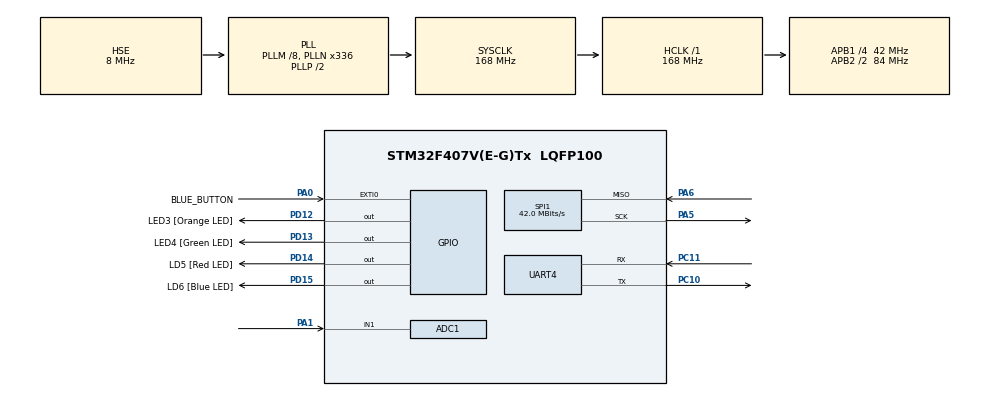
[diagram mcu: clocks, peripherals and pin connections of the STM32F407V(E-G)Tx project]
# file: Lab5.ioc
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ADC1.Channel-12\#ChannelRegularConversion=ADC_CHANNEL_1
ADC1.ClockPrescaler=ADC_CLOCK_SYNC_PCLK_DIV4
ADC1.ContinuousConvMode=DISABLE
ADC1.DMAContinuousRequests=DISABLE
ADC1.DataAlign=ADC_DATAALIGN_RIGHT
ADC1.DiscontinuousConvMode=DISABLE
ADC1.EOCSelection=ADC_EOC_SEQ_CONV
ADC1.EnableAnalogWatchDog=false
ADC1.ExternalTrigConv=ADC_EXTERNALTRIGCONV_T2_TRGO
ADC1.ExternalTrigConvEdge=ADC_EXTERNALTRIGCONVEDGE_RISING
ADC1.InjNumberOfConversion=0
ADC1.NbrOfConversion=1
ADC1.NbrOfConversionFlag=1
ADC1.Rank-12\#ChannelRegularConversion=1
ADC1.Resolution=ADC_RESOLUTION_12B
ADC1.SamplingTime-12\#ChannelRegularConversion=ADC_SAMPLETIME_480CYCLES
ADC1.ScanConvMode=DISABLE
ADC1.master=1
Dma.ADC1.0.Direction=DMA_PERIPH_TO_MEMORY
Dma.ADC1.0.FIFOMode=DMA_FIFOMODE_DISABLE
Dma.ADC1.0.Instance=DMA2_Stream0
Dma.ADC1.0.MemDataAlignment=DMA_MDATAALIGN_WORD
Dma.ADC1.0.MemInc=DMA_MINC_ENABLE
Dma.ADC1.0.Mode=DMA_CIRCULAR
Dma.ADC1.0.PeriphDataAlignment=DMA_PDATAALIGN_WORD
Dma.ADC1.0.PeriphInc=DMA_PINC_DISABLE
Dma.ADC1.0.Priority=DMA_PRIORITY_LOW
Dma.Request0=ADC1
Mcu.Family=STM32F4
Mcu.Name=STM32F407V(E-G)Tx
Mcu.Package=LQFP100
NVIC.ADC_IRQn=true\:0\:0\:false\:false\:true\:true
NVIC.DMA2_Stream0_IRQn=true\:0\:0\:false\:false\:true\:false
NVIC.EXTI0_IRQn=true\:0\:0\:false\:false\:true\:true
NVIC.PriorityGroup=NVIC_PRIORITYGROUP_4
NVIC.TIM2_IRQn=true\:0\:0\:true\:false\:true\:true
PA0-WKUP.GPIO_Label=BLUE_BUTTON
PA0-WKUP.Signal=GPXTI0
PA1.Signal=ADCx_IN1
PA5.Mode=RX_Only_Simplex_Unidirect_Master
PA5.Signal=SPI1_SCK
PA6.Mode=RX_Only_Simplex_Unidirect_Master
PA6.Signal=SPI1_MISO
PC10.Mode=Asynchronous
PC10.Signal=UART4_TX
PC11.Mode=Asynchronous
PC11.Signal=UART4_RX
PD12.GPIO_Label=LED3 [Orange LED]
PD12.Signal=GPIO_Output
PD13.GPIO_Label=LED4 [Green LED]
PD13.Signal=GPIO_Output
PD14.GPIO_Label=LD5 [Red LED]
PD14.Signal=GPIO_Output
PD15.GPIO_Label=LD6 [Blue LED]
PD15.Signal=GPIO_Output
PH0-OSC_IN.Mode=HSE-External-Oscillator
PH0-OSC_IN.Signal=RCC_OSC_IN
PH1-OSC_OUT.Mode=HSE-External-Oscillator
PH1-OSC_OUT.Signal=RCC_OSC_OUT
ProjectManager.HeapSize=0x200
ProjectManager.StackSize=0x400
ProjectManager.TargetToolchain=MDK-ARM V5
RCC.48MHZClocksFreq_Value=84000000
RCC.AHBFreq_Value=168000000
RCC.APB1CLKDivider=RCC_HCLK_DIV4
RCC.APB1Freq_Value=42000000
RCC.APB1TimFreq_Value=84000000
RCC.APB2CLKDivider=RCC_HCLK_DIV2
RCC.APB2Freq_Value=84000000
RCC.APB2TimFreq_Value=168000000
RCC.CortexFreq_Value=168000000
RCC.HCLKFreq_Value=168000000
RCC.HSE_VALUE=8000000
RCC.HSI_VALUE=16000000
RCC.LSE_VALUE=32768
RCC.PLLM=8
RCC.PLLN=336
RCC.PLLSourceVirtual=RCC_PLLSOURCE_HSE
RCC.SYSCLKFreq_VALUE=168000000
RCC.SYSCLKSource=RCC_SYSCLKSOURCE_PLLCLK
RCC.VCOOutputFreq_Value=336000000
SH.ADCx_IN1.0=ADC1_IN1,IN1
SPI1.CalculateBaudRate=42.0 MBits/s
SPI1.Direction=SPI_DIRECTION_2LINES_RXONLY
SPI1.Mode=SPI_MODE_MASTER
SPI1.VirtualType=VM_MASTER
TIM2.Period=1000
TIM2.Prescaler=1000
TIM2.TIM_MasterOutputTrigger=TIM_TRGO_UPDATE
UART4.VirtualMode=Asynchronous
VP_TIM2_VS_ClockSourceINT.Mode=Internal
board=Lab5

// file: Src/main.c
/**
  ******************************************************************************
  * File Name          : main.c
  * Description        : Main program body
  ******************************************************************************
  ** This notice applies to any and all portions of this file
  * that are not between comment pairs USER CODE BEGIN and
  * USER CODE END. Other portions of this file, whether
  * inserted by the user or by software development tools
  * are owned by their respective copyright owners.
  *
  * COPYRIGHT(c) 2018 STMicroelectronics
  *
  * Redistribution and use in source and binary forms, with or without modification,
  * are permitted provided that the following conditions are met:
  *   1. Redistributions of source code must retain the above copyright notice,
  *      this list of conditions and the following disclaimer.
  *   2. Redistributions in binary form must reproduce the above copyright notice,
  *      this list of conditions and the following disclaimer in the documentation
  *      and/or other materials provided with the distribution.
  *   3. Neither the name of STMicroelectronics nor the names of its contributors
  *      may be used to endorse or promote products derived from this software
  *      without specific prior written permission.
  *
  * THIS SOFTWARE IS PROVIDED BY THE COPYRIGHT HOLDERS AND CONTRIBUTORS "AS IS"
  * AND ANY EXPRESS OR IMPLIED WARRANTIES, INCLUDING, BUT NOT LIMITED TO, THE
  * IMPLIED WARRANTIES OF MERCHANTABILITY AND FITNESS FOR A PARTICULAR PURPOSE ARE
  * DISCLAIMED. IN NO EVENT SHALL THE COPYRIGHT HOLDER OR CONTRIBUTORS BE LIABLE
  * FOR ANY DIRECT, INDIRECT, INCIDENTAL, SPECIAL, EXEMPLARY, OR CONSEQUENTIAL
  * DAMAGES (INCLUDING, BUT NOT LIMITED TO, PROCUREMENT OF SUBSTITUTE GOODS OR
  * SERVICES; LOSS OF USE, DATA, OR PROFITS; OR BUSINESS INTERRUPTION) HOWEVER
  * CAUSED AND ON ANY THEORY OF LIABILITY, WHETHER IN CONTRACT, STRICT LIABILITY,
  * OR TORT (INCLUDING NEGLIGENCE OR OTHERWISE) ARISING IN ANY WAY OUT OF THE USE
  * OF THIS SOFTWARE, EVEN IF ADVISED OF THE POSSIBILITY OF SUCH DAMAGE.
  *
  ******************************************************************************
  */
#include "main.h"
#include "stm32f4xx_hal.h"
#include "lis3dsh.h"

#define STATE_NOTHING 0
#define STATE_TAP 1
#define STATE_DOUBLETAP 2
#define STATE_SINGLETAP 3

#define X_THRESH 100
#define Y_THRESH 100
#define Z_THRESH 30

#define ACC_SAMPLE_PERIOD_MS 1
#define FSM_FREQUENCY_MS 50
#define BUF_LENGTH FSM_FREQUENCY_MS / ACC_SAMPLE_PERIOD_MS

#define ADC_BUFFER_SIZE 8400

ADC_HandleTypeDef hadc1;
DMA_HandleTypeDef hdma_adc1;

SPI_HandleTypeDef hspi1;

TIM_HandleTypeDef htim2;

UART_HandleTypeDef huart4;

uint8_t status;
float Buffer[3];
float accX, accY, accZ;
uint8_t MyFlag = 0;
uint8_t state = STATE_NOTHING;
uint32_t click_timer = 0;
LIS3DSH_InitTypeDef 		Acc_instance;

void SystemClock_Config(void);
static void MX_GPIO_Init(void);
static void MX_DMA_Init(void);
static void MX_ADC1_Init(void);
static void MX_TIM2_Init(void);
static void MX_UART4_Init(void);
static void MX_SPI1_Init(void);

void initializeACC (void);
void start_adc(void);
void stop_adc(void);

uint8_t detected_tap(float *, int);

float buf[BUF_LENGTH];
uint8_t buf_index = 0;

uint32_t ADCBufferDMA[ADC_BUFFER_SIZE];

int main(void)
{

  HAL_Init();
  SystemClock_Config();
  MX_GPIO_Init();
  MX_DMA_Init();
  MX_ADC1_Init();
  MX_TIM2_Init();
  MX_UART4_Init();
  MX_SPI1_Init();
	initializeACC	();	// Like any other peripheral, you need to initialize it. Refer to the its driver to learn more.

	// and example of sending a data through UART, but you need to configure the UART block:
	// HAL_UART_Transmit(&huart2,"FinalProject\n",14,2000);

	printf("Starting while\n");
	float lastZ = 0.0;
	float lastY = 0.0;
	float lastX = 0.0;
	float minZ, maxZ;
	float maxDrop, minDrop;
	minZ = 100000.0f;
	maxZ = 100.0f;
	maxDrop = minDrop = 0;
  while (1)
  {

		if (MyFlag)
		{
			//HAL_GPIO_TogglePin(GPIOD, LD6_Pin);
			MyFlag = 0;
			//Reading the accelerometer status register
				LIS3DSH_Read (&status, LIS3DSH_STATUS, 1);
				//The first four bits denote if we have new data on all XYZ axes,
		   	//Z axis only, Y axis only or Z axis only. If any or all changed, proceed
				if ((status & 0x0F) != 0x00)
				{
					LIS3DSH_ReadACC(&Buffer[0]);
					accX = (float)Buffer[0];
					accY = (float)Buffer[1];
					accZ = (float)Buffer[2];
				}

				buf[(buf_index++) % BUF_LENGTH] = accZ;

				if(accZ > maxZ) maxZ = accZ;
				else if(accZ < minZ) minZ = accZ;

				if(click_timer/100) {
					click_timer = 0;
					HAL_GPIO_TogglePin(GPIOD, LD4_Pin);
					float deltaZ = maxZ - minZ;
					maxZ = -5.0f;
					minZ = 100000.0f;
					maxDrop = minDrop = 0;
					//MyFlag = 0;
					uint8_t tap = detected_tap(buf, BUF_LENGTH);

					switch(state) {
						case STATE_NOTHING:
							if(tap) state = STATE_TAP;
							break;
						case STATE_TAP:
							if(tap) state = STATE_DOUBLETAP;
							else state = STATE_SINGLETAP;
							break;
						case STATE_DOUBLETAP:
							HAL_GPIO_TogglePin(GPIOD, LD3_Pin);
							state = STATE_NOTHING;
							break;
						case STATE_SINGLETAP:
							HAL_GPIO_TogglePin(GPIOD, LD6_Pin);
							state = STATE_NOTHING;
							break;
						default:
							break;
					}
					lastX = accX;
					lastY = accY;
					lastZ = accZ;
			}
		}
  }
}

uint8_t detected_tap(float *samples, int num_samples) {
	float max = samples[0];
	int c;
	for(c = 1; c < num_samples; c++) {
		if(samples[c] > max) {
			max = samples[c];
		}
	}
	if(max - samples[0] > Z_THRESH && max - samples[num_samples - 1] > Z_THRESH) {
		return 1;
	}
	return 0;
}

/** System Clock Configuration
*/
void SystemClock_Config(void)
{

  RCC_OscInitTypeDef RCC_OscInitStruct;
  RCC_ClkInitTypeDef RCC_ClkInitStruct;

    /**Configure the main internal regulator output voltage
    */
  __HAL_RCC_PWR_CLK_ENABLE();

  __HAL_PWR_VOLTAGESCALING_CONFIG(PWR_REGULATOR_VOLTAGE_SCALE1);

    /**Initializes the CPU, AHB and APB busses clocks
    */
  RCC_OscInitStruct.OscillatorType = RCC_OSCILLATORTYPE_HSE;
  RCC_OscInitStruct.HSEState = RCC_HSE_ON;
  RCC_OscInitStruct.PLL.PLLState = RCC_PLL_ON;
  RCC_OscInitStruct.PLL.PLLSource = RCC_PLLSOURCE_HSE;
  RCC_OscInitStruct.PLL.PLLM = 8;
  RCC_OscInitStruct.PLL.PLLN = 336;
  RCC_OscInitStruct.PLL.PLLP = RCC_PLLP_DIV2;
  RCC_OscInitStruct.PLL.PLLQ = 7;
  if (HAL_RCC_OscConfig(&RCC_OscInitStruct) != HAL_OK)
  {
    _Error_Handler(__FILE__, __LINE__);
  }

    /**Initializes the CPU, AHB and APB busses clocks
    */
  RCC_ClkInitStruct.ClockType = RCC_CLOCKTYPE_HCLK|RCC_CLOCKTYPE_SYSCLK
                              |RCC_CLOCKTYPE_PCLK1|RCC_CLOCKTYPE_PCLK2;
  RCC_ClkInitStruct.SYSCLKSource = RCC_SYSCLKSOURCE_PLLCLK;
  RCC_ClkInitStruct.AHBCLKDivider = RCC_SYSCLK_DIV1;
  RCC_ClkInitStruct.APB1CLKDivider = RCC_HCLK_DIV4;
  RCC_ClkInitStruct.APB2CLKDivider = RCC_HCLK_DIV2;

  if (HAL_RCC_ClockConfig(&RCC_ClkInitStruct, FLASH_LATENCY_5) != HAL_OK)
  {
    _Error_Handler(__FILE__, __LINE__);
  }

    /**Configure the Systick interrupt time
    */
  HAL_SYSTICK_Config(HAL_RCC_GetHCLKFreq()/1000);

    /**Configure the Systick
    */
  HAL_SYSTICK_CLKSourceConfig(SYSTICK_CLKSOURCE_HCLK);

  /* SysTick_IRQn interrupt configuration */
  HAL_NVIC_SetPriority(SysTick_IRQn, 0, 0);
}

/** Configure pins as
        * Analog
        * Input
        * Output
        * EVENT_OUT
        * EXTI
     PC3   ------> I2S2_SD
     PA4   ------> I2S3_WS
     PA5   ------> SPI1_SCK
     PA6   ------> SPI1_MISO
     PA7   ------> SPI1_MOSI
     PB10   ------> I2S2_CK
     PC7   ------> I2S3_MCK
     PA9   ------> USB_OTG_FS_VBUS
     PA10   ------> USB_OTG_FS_ID
     PA11   ------> USB_OTG_FS_DM
     PA12   ------> USB_OTG_FS_DP
     PC10   ------> I2S3_CK
     PC12   ------> I2S3_SD
     PB6   ------> I2C1_SCL
     PB9   ------> I2C1_SDA
*/
/* ADC1 init function */
static void MX_ADC1_Init(void)
{

  ADC_ChannelConfTypeDef sConfig;

    /**Configure the global features of the ADC (Clock, Resolution, Data Alignment and number of conversion)
    */
  hadc1.Instance = ADC1;
  hadc1.Init.ClockPrescaler = ADC_CLOCK_SYNC_PCLK_DIV4;
  hadc1.Init.Resolution = ADC_RESOLUTION_12B;
  hadc1.Init.ScanConvMode = DISABLE;
  hadc1.Init.ContinuousConvMode = DISABLE;
  hadc1.Init.DiscontinuousConvMode = DISABLE;
  hadc1.Init.ExternalTrigConvEdge = ADC_EXTERNALTRIGCONVEDGE_RISING;
  hadc1.Init.ExternalTrigConv = ADC_EXTERNALTRIGCONV_T2_TRGO;
  hadc1.Init.DataAlign = ADC_DATAALIGN_RIGHT;
  hadc1.Init.NbrOfConversion = 1;
  hadc1.Init.DMAContinuousRequests = DISABLE;
  hadc1.Init.EOCSelection = ADC_EOC_SEQ_CONV;
  if (HAL_ADC_Init(&hadc1) != HAL_OK)
  {
    _Error_Handler(__FILE__, __LINE__);
  }

    /**Configure for the selected ADC regular channel its corresponding rank in the sequencer and its sample time.
    */
  sConfig.Channel = ADC_CHANNEL_1;
  sConfig.Rank = 1;
  sConfig.SamplingTime = ADC_SAMPLETIME_480CYCLES;
  if (HAL_ADC_ConfigChannel(&hadc1, &sConfig) != HAL_OK)
  {
    _Error_Handler(__FILE__, __LINE__);
  }

}

/* SPI1 init function */
static void MX_SPI1_Init(void)
{

  /* SPI1 parameter configuration*/
  hspi1.Instance = SPI1;
  hspi1.Init.Mode = SPI_MODE_MASTER;
  hspi1.Init.Direction = SPI_DIRECTION_2LINES_RXONLY;
  hspi1.Init.DataSize = SPI_DATASIZE_8BIT;
  hspi1.Init.CLKPolarity = SPI_POLARITY_LOW;
  hspi1.Init.CLKPhase = SPI_PHASE_1EDGE;
  hspi1.Init.NSS = SPI_NSS_SOFT;
  hspi1.Init.BaudRatePrescaler = SPI_BAUDRATEPRESCALER_2;
  hspi1.Init.FirstBit = SPI_FIRSTBIT_MSB;
  hspi1.Init.TIMode = SPI_TIMODE_DISABLE;
  hspi1.Init.CRCCalculation = SPI_CRCCALCULATION_DISABLE;
  hspi1.Init.CRCPolynomial = 10;
  if (HAL_SPI_Init(&hspi1) != HAL_OK)
  {
    _Error_Handler(__FILE__, __LINE__);
  }

}

/* TIM2 init function */
static void MX_TIM2_Init(void)
{

  TIM_ClockConfigTypeDef sClockSourceConfig;
  TIM_MasterConfigTypeDef sMasterConfig;

  htim2.Instance = TIM2;
  htim2.Init.Prescaler = 1000;
  htim2.Init.CounterMode = TIM_COUNTERMODE_UP;
  htim2.Init.Period = 1000;
  htim2.Init.ClockDivision = TIM_CLOCKDIVISION_DIV1;
  if (HAL_TIM_Base_Init(&htim2) != HAL_OK)
  {
    _Error_Handler(__FILE__, __LINE__);
  }

  sClockSourceConfig.ClockSource = TIM_CLOCKSOURCE_INTERNAL;
  if (HAL_TIM_ConfigClockSource(&htim2, &sClockSourceConfig) != HAL_OK)
  {
    _Error_Handler(__FILE__, __LINE__);
  }

  sMasterConfig.MasterOutputTrigger = TIM_TRGO_UPDATE;
  sMasterConfig.MasterSlaveMode = TIM_MASTERSLAVEMODE_DISABLE;
  if (HAL_TIMEx_MasterConfigSynchronization(&htim2, &sMasterConfig) != HAL_OK)
  {
    _Error_Handler(__FILE__, __LINE__);
  }

}

/* UART4 init function */
static void MX_UART4_Init(void)
{

  huart4.Instance = UART4;
  huart4.Init.BaudRate = 115200;
  huart4.Init.WordLength = UART_WORDLENGTH_8B;
  huart4.Init.StopBits = UART_STOPBITS_1;
  huart4.Init.Parity = UART_PARITY_NONE;
  huart4.Init.Mode = UART_MODE_TX_RX;
  huart4.Init.HwFlowCtl = UART_HWCONTROL_NONE;
  huart4.Init.OverSampling = UART_OVERSAMPLING_16;
  if (HAL_UART_Init(&huart4) != HAL_OK)
  {
    _Error_Handler(__FILE__, __LINE__);
  }

}

static void MX_DMA_Init(void)
{
  /* DMA controller clock enable */
  __HAL_RCC_DMA2_CLK_ENABLE();

  /* DMA interrupt init */
  /* DMA2_Stream0_IRQn interrupt configuration */
  HAL_NVIC_SetPriority(DMA2_Stream0_IRQn, 0, 0);
  HAL_NVIC_EnableIRQ(DMA2_Stream0_IRQn);

}
static void MX_GPIO_Init(void)
{

  GPIO_InitTypeDef GPIO_InitStruct;

  /* GPIO Ports Clock Enable */
  __HAL_RCC_GPIOE_CLK_ENABLE();
  __HAL_RCC_GPIOC_CLK_ENABLE();
  __HAL_RCC_GPIOH_CLK_ENABLE();
  __HAL_RCC_GPIOA_CLK_ENABLE();
  __HAL_RCC_GPIOB_CLK_ENABLE();
  __HAL_RCC_GPIOD_CLK_ENABLE();

  /*Configure GPIO pin Output Level */
  HAL_GPIO_WritePin(CS_I2C_SPI_GPIO_Port, CS_I2C_SPI_Pin, GPIO_PIN_RESET);

  /*Configure GPIO pin Output Level */
  HAL_GPIO_WritePin(OTG_FS_PowerSwitchOn_GPIO_Port, OTG_FS_PowerSwitchOn_Pin, GPIO_PIN_SET);

  /*Configure GPIO pin Output Level */
  HAL_GPIO_WritePin(GPIOD, LD4_Pin|LD3_Pin|LD5_Pin|LD6_Pin
                          |Audio_RST_Pin, GPIO_PIN_RESET);

  /*Configure GPIO pin : CS_I2C_SPI_Pin */
  GPIO_InitStruct.Pin = CS_I2C_SPI_Pin;
  GPIO_InitStruct.Mode = GPIO_MODE_OUTPUT_PP;
  GPIO_InitStruct.Pull = GPIO_NOPULL;
  GPIO_InitStruct.Speed = GPIO_SPEED_FREQ_LOW;
  HAL_GPIO_Init(CS_I2C_SPI_GPIO_Port, &GPIO_InitStruct);

  /*Configure GPIO pin : OTG_FS_PowerSwitchOn_Pin */
  GPIO_InitStruct.Pin = OTG_FS_PowerSwitchOn_Pin;
  GPIO_InitStruct.Mode = GPIO_MODE_OUTPUT_PP;
  GPIO_InitStruct.Pull = GPIO_NOPULL;
  GPIO_InitStruct.Speed = GPIO_SPEED_FREQ_LOW;
  HAL_GPIO_Init(OTG_FS_PowerSwitchOn_GPIO_Port, &GPIO_InitStruct);

  /*Configure GPIO pin : PDM_OUT_Pin */
  GPIO_InitStruct.Pin = PDM_OUT_Pin;
  GPIO_InitStruct.Mode = GPIO_MODE_AF_PP;
  GPIO_InitStruct.Pull = GPIO_NOPULL;
  GPIO_InitStruct.Speed = GPIO_SPEED_FREQ_LOW;
  GPIO_InitStruct.Alternate = GPIO_AF5_SPI2;
  HAL_GPIO_Init(PDM_OUT_GPIO_Port, &GPIO_InitStruct);

  /*Configure GPIO pin : B1_Pin */
  GPIO_InitStruct.Pin = B1_Pin;
  GPIO_InitStruct.Mode = GPIO_MODE_IT_RISING;
  GPIO_InitStruct.Pull = GPIO_NOPULL;
  HAL_GPIO_Init(B1_GPIO_Port, &GPIO_InitStruct);

  /*Configure GPIO pin : I2S3_WS_Pin */
  GPIO_InitStruct.Pin = I2S3_WS_Pin;
  GPIO_InitStruct.Mode = GPIO_MODE_AF_PP;
  GPIO_InitStruct.Pull = GPIO_NOPULL;
  GPIO_InitStruct.Speed = GPIO_SPEED_FREQ_LOW;
  GPIO_InitStruct.Alternate = GPIO_AF6_SPI3;
  HAL_GPIO_Init(I2S3_WS_GPIO_Port, &GPIO_InitStruct);

  /*Configure GPIO pins : SPI1_SCK_Pin SPI1_MISO_Pin SPI1_MOSI_Pin */
  GPIO_InitStruct.Pin = SPI1_SCK_Pin|SPI1_MISO_Pin|SPI1_MOSI_Pin;
  GPIO_InitStruct.Mode = GPIO_MODE_AF_PP;
  GPIO_InitStruct.Pull = GPIO_NOPULL;
  GPIO_InitStruct.Speed = GPIO_SPEED_FREQ_LOW;
  GPIO_InitStruct.Alternate = GPIO_AF5_SPI1;
  HAL_GPIO_Init(GPIOA, &GPIO_InitStruct);

  /*Configure GPIO pin : BOOT1_Pin */
  GPIO_InitStruct.Pin = BOOT1_Pin;
  GPIO_InitStruct.Mode = GPIO_MODE_INPUT;
  GPIO_InitStruct.Pull = GPIO_NOPULL;
  HAL_GPIO_Init(BOOT1_GPIO_Port, &GPIO_InitStruct);

  /*Configure GPIO pin : CLK_IN_Pin */
  GPIO_InitStruct.Pin = CLK_IN_Pin;
  GPIO_InitStruct.Mode = GPIO_MODE_AF_PP;
  GPIO_InitStruct.Pull = GPIO_NOPULL;
  GPIO_InitStruct.Speed = GPIO_SPEED_FREQ_LOW;
  GPIO_InitStruct.Alternate = GPIO_AF5_SPI2;
  HAL_GPIO_Init(CLK_IN_GPIO_Port, &GPIO_InitStruct);

  /*Configure GPIO pins : LD4_Pin LD3_Pin LD5_Pin LD6_Pin
                           Audio_RST_Pin */
  GPIO_InitStruct.Pin = LD4_Pin|LD3_Pin|LD5_Pin|LD6_Pin
                          |Audio_RST_Pin;
  GPIO_InitStruct.Mode = GPIO_MODE_OUTPUT_PP;
  GPIO_InitStruct.Pull = GPIO_NOPULL;
  GPIO_InitStruct.Speed = GPIO_SPEED_FREQ_LOW;
  HAL_GPIO_Init(GPIOD, &GPIO_InitStruct);

  /*Configure GPIO pins : I2S3_MCK_Pin I2S3_SCK_Pin I2S3_SD_Pin */
  GPIO_InitStruct.Pin = I2S3_MCK_Pin|I2S3_SCK_Pin|I2S3_SD_Pin;
  GPIO_InitStruct.Mode = GPIO_MODE_AF_PP;
  GPIO_InitStruct.Pull = GPIO_NOPULL;
  GPIO_InitStruct.Speed = GPIO_SPEED_FREQ_LOW;
  GPIO_InitStruct.Alternate = GPIO_AF6_SPI3;
  HAL_GPIO_Init(GPIOC, &GPIO_InitStruct);

  /*Configure GPIO pin : VBUS_FS_Pin */
  GPIO_InitStruct.Pin = VBUS_FS_Pin;
  GPIO_InitStruct.Mode = GPIO_MODE_INPUT;
  GPIO_InitStruct.Pull = GPIO_NOPULL;
  HAL_GPIO_Init(VBUS_FS_GPIO_Port, &GPIO_InitStruct);

  /*Configure GPIO pins : OTG_FS_ID_Pin OTG_FS_DM_Pin OTG_FS_DP_Pin */
  GPIO_InitStruct.Pin = OTG_FS_ID_Pin|OTG_FS_DM_Pin|OTG_FS_DP_Pin;
  GPIO_InitStruct.Mode = GPIO_MODE_AF_PP;
  GPIO_InitStruct.Pull = GPIO_NOPULL;
  GPIO_InitStruct.Speed = GPIO_SPEED_FREQ_LOW;
  GPIO_InitStruct.Alternate = GPIO_AF10_OTG_FS;
  HAL_GPIO_Init(GPIOA, &GPIO_InitStruct);

  /*Configure GPIO pin : OTG_FS_OverCurrent_Pin */
  GPIO_InitStruct.Pin = OTG_FS_OverCurrent_Pin;
  GPIO_InitStruct.Mode = GPIO_MODE_INPUT;
  GPIO_InitStruct.Pull = GPIO_NOPULL;
  HAL_GPIO_Init(OTG_FS_OverCurrent_GPIO_Port, &GPIO_InitStruct);

  /*Configure GPIO pins : Audio_SCL_Pin Audio_SDA_Pin */
  GPIO_InitStruct.Pin = Audio_SCL_Pin|Audio_SDA_Pin;
  GPIO_InitStruct.Mode = GPIO_MODE_AF_OD;
  GPIO_InitStruct.Pull = GPIO_PULLUP;
  GPIO_InitStruct.Speed = GPIO_SPEED_FREQ_LOW;
  GPIO_InitStruct.Alternate = GPIO_AF4_I2C1;
  HAL_GPIO_Init(GPIOB, &GPIO_InitStruct);

  /*Configure GPIO pin : MEMS_INT2_Pin */
  GPIO_InitStruct.Pin = MEMS_INT2_Pin;
  GPIO_InitStruct.Mode = GPIO_MODE_EVT_RISING;
  GPIO_InitStruct.Pull = GPIO_NOPULL;
  HAL_GPIO_Init(MEMS_INT2_GPIO_Port, &GPIO_InitStruct);

}

/* USER CODE BEGIN 4 */

void initializeACC(void){

	Acc_instance.Axes_Enable				= LIS3DSH_XYZ_ENABLE;
	Acc_instance.AA_Filter_BW				= LIS3DSH_AA_BW_50;
	Acc_instance.Full_Scale					= LIS3DSH_FULLSCALE_2;
	Acc_instance.Power_Mode_Output_DataRate		= LIS3DSH_DATARATE_100;
	Acc_instance.Self_Test					= LIS3DSH_SELFTEST_NORMAL;
	Acc_instance.Continous_Update   = LIS3DSH_ContinousUpdate_Disabled;

	LIS3DSH_Init(&Acc_instance);

	/* Enabling interrupt conflicts with push button
  ACC_Interrupt_Config.Dataready_Interrupt	= LIS3DSH_DATA_READY_INTERRUPT_ENABLED;
	ACC_Interrupt_Config.Interrupt_signal			= LIS3DSH_ACTIVE_HIGH_INTERRUPT_SIGNAL;
	ACC_Interrupt_Config.Interrupt_type				= LIS3DSH_INTERRUPT_REQUEST_PULSED;

	LIS3DSH_DataReadyInterruptConfig(&ACC_Interrupt_Config);
	*/
}

void start_adc(void) {
	HAL_ADC_Start_DMA(&hadc1, ADCBufferDMA, ADC_BUFFER_SIZE);
}

void stop_adc(void) {
	HAL_ADC_Stop_DMA(&hadc1);
}

void HAL_ADC_ConvCpltCallback(ADC_HandleTypeDef *hadc) {
	stop_adc();

	/* SEND DATA */
//	char send[9];
	HAL_UART_Transmit(&huart4, (uint8_t *) ADCBufferDMA, ADC_BUFFER_SIZE * sizeof(uint32_t), 1000);
}

/* USER CODE END 4 */

void _Error_Handler(char * file, int line)
{
  while(1)
  {
  }
}

/************************ (C) COPYRIGHT STMicroelectronics *****END OF FILE****/
